VERSION 5.8 ;
BUSBITCHARS "[]" ;
DIVIDERCHAR "/" ;
UNITS
    DATABASE MICRONS 1000 ;
END UNITS

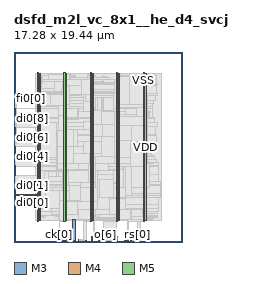
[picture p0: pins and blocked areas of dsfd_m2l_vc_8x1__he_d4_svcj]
MACRO dsfd_m2l_vc_8x1__he_d4_svcj
  FOREIGN dsfd_m2l_vc_8x1__he_d4_svcj 0 0 ;
  CLASS BLOCK ;
  SIZE 17.28 BY 19.44 ;
  PIN ck[0]
    DIRECTION INPUT ;
    USE SIGNAL ;
    PORT
      LAYER M3 ;
        RECT  4.644 0 4.662 0.144 ;
    END
    PORT
      LAYER M3 ;
        RECT  4.644 0.108 4.662 0.173 ;
    END
  END ck[0]
  PIN di0[0]
    DIRECTION INPUT ;
    USE SIGNAL ;
    PORT
      LAYER M4 ;
        RECT  0 4.8 0.192 4.824 ;
    END
    PORT
      LAYER M4 ;
        RECT  0.156 4.8 2.408 4.824 ;
    END
  END di0[0]
  PIN di0[1]
    DIRECTION INPUT ;
    USE SIGNAL ;
    PORT
      LAYER M4 ;
        RECT  0 5.808 0.192 5.832 ;
    END
  END di0[1]
  PIN di0[2]
    DIRECTION INPUT ;
    USE SIGNAL ;
    PORT
      LAYER M4 ;
        RECT  0 6.768 0.192 6.792 ;
    END
  END di0[2]
  PIN di0[3]
    DIRECTION INPUT ;
    USE SIGNAL ;
    PORT
      LAYER M4 ;
        RECT  0 7.776 0.192 7.8 ;
    END
  END di0[3]
  PIN di0[4]
    DIRECTION INPUT ;
    USE SIGNAL ;
    PORT
      LAYER M4 ;
        RECT  0 8.736 0.192 8.76 ;
    END
  END di0[4]
  PIN di0[5]
    DIRECTION INPUT ;
    USE SIGNAL ;
    PORT
      LAYER M4 ;
        RECT  0 9.744 0.192 9.768 ;
    END
  END di0[5]
  PIN di0[6]
    DIRECTION INPUT ;
    USE SIGNAL ;
    PORT
      LAYER M4 ;
        RECT  0 10.704 0.192 10.728 ;
    END
  END di0[6]
  PIN di0[7]
    DIRECTION INPUT ;
    USE SIGNAL ;
    PORT
      LAYER M4 ;
        RECT  0 11.712 0.192 11.736 ;
    END
  END di0[7]
  PIN di0[8]
    DIRECTION INPUT ;
    USE SIGNAL ;
    PORT
      LAYER M4 ;
        RECT  0 12.672 0.192 12.696 ;
    END
  END di0[8]
  PIN di0[9]
    DIRECTION INPUT ;
    USE SIGNAL ;
    PORT
      LAYER M4 ;
        RECT  0 13.68 0.192 13.704 ;
    END
  END di0[9]
  PIN fi0[0]
    DIRECTION INPUT ;
    USE SIGNAL ;
    PORT
      LAYER M4 ;
        RECT  0 14.64 0.192 14.664 ;
    END
  END fi0[0]
  PIN o[0]
    DIRECTION OUTPUT ;
    USE SIGNAL ;
    PORT
      LAYER M5 ;
        RECT  5.328 0 5.352 0.192 ;
    END
    PORT
      LAYER M5 ;
        RECT  4.656 0.144 5.352 0.323 ;
    END
  END o[0]
  PIN o[10]
    DIRECTION OUTPUT ;
    USE SIGNAL ;
    PORT
      LAYER M5 ;
        RECT  11.952 0 11.976 0.192 ;
    END
    PORT
      LAYER M5 ;
        RECT  11.952 0.144 11.976 0.227 ;
    END
  END o[10]
  PIN o[1]
    DIRECTION OUTPUT ;
    USE SIGNAL ;
    PORT
      LAYER M3 ;
        RECT  5.976 0 5.994 0.144 ;
    END
    PORT
      LAYER M3 ;
        RECT  5.976 0.108 5.994 0.139 ;
    END
    PORT
      LAYER M3 ;
        RECT  5.976 0.139 6.318 2.263 ;
    END
  END o[1]
  PIN o[2]
    DIRECTION OUTPUT ;
    USE SIGNAL ;
    PORT
      LAYER M5 ;
        RECT  6.624 0 6.648 0.192 ;
    END
    PORT
      LAYER M5 ;
        RECT  6.624 0.144 6.648 0.227 ;
    END
  END o[2]
  PIN o[3]
    DIRECTION OUTPUT ;
    USE SIGNAL ;
    PORT
      LAYER M3 ;
        RECT  7.308 0 7.326 0.144 ;
    END
    PORT
      LAYER M3 ;
        RECT  7.308 0.108 7.326 0.139 ;
    END
    PORT
      LAYER M3 ;
        RECT  7.308 0.139 7.398 0.187 ;
    END
  END o[3]
  PIN o[4]
    DIRECTION OUTPUT ;
    USE SIGNAL ;
    PORT
      LAYER M5 ;
        RECT  7.968 0 7.992 0.192 ;
    END
    PORT
      LAYER M5 ;
        RECT  7.968 0.144 7.992 0.563 ;
    END
  END o[4]
  PIN o[5]
    DIRECTION OUTPUT ;
    USE SIGNAL ;
    PORT
      LAYER M3 ;
        RECT  8.64 0 8.658 0.144 ;
    END
    PORT
      LAYER M3 ;
        RECT  8.64 0.108 8.658 0.139 ;
    END
    PORT
      LAYER M3 ;
        RECT  8.64 0.139 9.162 0.167 ;
    END
  END o[5]
  PIN o[6]
    DIRECTION OUTPUT ;
    USE SIGNAL ;
    PORT
      LAYER M5 ;
        RECT  9.312 0 9.336 0.192 ;
    END
    PORT
      LAYER M5 ;
        RECT  9.312 0.144 9.336 0.227 ;
    END
  END o[6]
  PIN o[7]
    DIRECTION OUTPUT ;
    USE SIGNAL ;
    PORT
      LAYER M3 ;
        RECT  9.972 0 9.99 0.144 ;
    END
    PORT
      LAYER M3 ;
        RECT  9.972 0.108 9.99 0.139 ;
    END
    PORT
      LAYER M3 ;
        RECT  9.972 0.139 10.386 0.187 ;
    END
  END o[7]
  PIN o[8]
    DIRECTION OUTPUT ;
    USE SIGNAL ;
    PORT
      LAYER M5 ;
        RECT  10.608 0 10.632 0.192 ;
    END
    PORT
      LAYER M5 ;
        RECT  10.608 0.144 10.632 0.563 ;
    END
  END o[8]
  PIN o[9]
    DIRECTION OUTPUT ;
    USE SIGNAL ;
    PORT
      LAYER M3 ;
        RECT  11.304 0 11.322 0.144 ;
    END
    PORT
      LAYER M3 ;
        RECT  11.304 0.108 11.322 0.139 ;
    END
    PORT
      LAYER M3 ;
        RECT  11.304 0.139 11.682 0.167 ;
    END
  END o[9]
  PIN rs[0]
    DIRECTION INPUT ;
    USE SIGNAL ;
    PORT
      LAYER M3 ;
        RECT  12.636 0 12.654 0.144 ;
    END
    PORT
      LAYER M3 ;
        RECT  12.636 0.108 12.654 0.187 ;
    END
  END rs[0]
  PIN VDD
    DIRECTION INOUT ;
    USE POWER ;
    PORT
      LAYER M5 ;
        RECT  13.392 2.151 13.512 17.289 ;
        RECT  10.692 2.151 10.812 17.289 ;
        RECT  7.992 2.151 8.112 17.289 ;
        RECT  5.292 2.151 5.412 17.289 ;
        RECT  2.592 2.151 2.712 17.289 ;
    END
  END VDD
  PIN VSS
    DIRECTION INOUT ;
    USE GROUND ;
    PORT
      LAYER M5 ;
        RECT  13.2 2.137 13.32 17.303 ;
        RECT  10.5 2.137 10.62 17.303 ;
        RECT  7.8 2.137 7.92 17.303 ;
        RECT  5.1 2.137 5.22 17.303 ;
        RECT  2.4 2.137 2.52 17.303 ;
    END
  END VSS
  # OT_OBS_CLOSED layer=M5 d_um=1.536 added=44
  OBS
    LAYER RVTN ;
     RECT  2.16 2.16 15.12 2.295 ;
     RECT  2.16 2.565 15.12 2.835 ;
     RECT  2.16 3.105 15.12 3.375 ;
     RECT  2.16 3.645 15.12 3.915 ;
     RECT  2.16 4.185 15.12 4.455 ;
     RECT  2.16 4.725 15.12 4.995 ;
     RECT  2.16 5.265 15.12 5.535 ;
     RECT  2.16 5.805 15.12 6.075 ;
     RECT  2.16 6.345 15.12 6.615 ;
     RECT  2.16 6.885 15.12 7.155 ;
     RECT  2.16 7.425 15.12 7.695 ;
     RECT  2.16 7.965 15.12 8.235 ;
     RECT  2.16 8.505 15.12 8.775 ;
     RECT  2.16 9.045 15.12 9.315 ;
     RECT  2.16 9.585 15.12 9.855 ;
     RECT  2.16 10.125 15.12 10.395 ;
     RECT  2.16 10.665 15.12 10.935 ;
     RECT  2.16 11.205 15.12 11.475 ;
     RECT  2.16 11.745 15.12 12.015 ;
     RECT  2.16 12.285 15.12 12.555 ;
     RECT  2.16 12.825 15.12 13.095 ;
     RECT  2.16 13.365 15.12 13.635 ;
     RECT  2.16 13.905 15.12 14.175 ;
     RECT  2.16 14.445 15.12 14.715 ;
     RECT  2.16 14.985 15.12 15.255 ;
     RECT  2.16 15.525 15.12 15.795 ;
     RECT  2.16 16.065 15.12 16.335 ;
     RECT  2.16 16.605 15.12 16.875 ;
     RECT  2.16 17.145 15.12 17.28 ;
    LAYER RVTP ;
     RECT  2.16 2.295 15.12 2.565 ;
     RECT  2.16 2.835 15.12 3.105 ;
     RECT  2.16 3.375 15.12 3.645 ;
     RECT  2.16 3.915 15.12 4.185 ;
     RECT  2.16 4.455 15.12 4.725 ;
     RECT  2.16 4.995 15.12 5.265 ;
     RECT  2.16 5.535 15.12 5.805 ;
     RECT  2.16 6.075 15.12 6.345 ;
     RECT  2.16 6.615 15.12 6.885 ;
     RECT  2.16 7.155 15.12 7.425 ;
     RECT  2.16 7.695 15.12 7.965 ;
     RECT  2.16 8.235 15.12 8.505 ;
     RECT  2.16 8.775 15.12 9.045 ;
     RECT  2.16 9.315 15.12 9.585 ;
     RECT  2.16 9.855 15.12 10.125 ;
     RECT  2.16 10.395 15.12 10.665 ;
     RECT  2.16 10.935 15.12 11.205 ;
     RECT  2.16 11.475 15.12 11.745 ;
     RECT  2.16 12.015 15.12 12.285 ;
     RECT  2.16 12.555 15.12 12.825 ;
     RECT  2.16 13.095 15.12 13.365 ;
     RECT  2.16 13.635 15.12 13.905 ;
     RECT  2.16 14.175 15.12 14.445 ;
     RECT  2.16 14.715 15.12 14.985 ;
     RECT  2.16 15.255 15.12 15.525 ;
     RECT  2.16 15.795 15.12 16.065 ;
     RECT  2.16 16.335 15.12 16.605 ;
     RECT  2.16 16.875 15.12 17.145 ;
    LAYER M1 ;
     RECT  2.16 2.151 15.12 17.289 ;
    LAYER M2 ;
     RECT  5.971 0.144 6.323 0.162 ;
     RECT  7.303 0.144 7.403 0.162 ;
     RECT  8.635 0.144 9.167 0.162 ;
     RECT  9.967 0.144 10.391 0.162 ;
     RECT  11.299 0.144 11.687 0.162 ;
     RECT  2.16 2.151 12.343 17.289 ;
     RECT  12.343 2.106 12.659 17.289 ;
     RECT  12.659 2.151 15.12 17.289 ;
    LAYER M3 ;
     RECT  9.144 0.167 9.162 0.187 ;
     RECT  9.144 0.187 10.386 0.523 ;
     RECT  11.664 0.167 11.682 2.101 ;
     RECT  12.636 0.187 12.978 2.101 ;
     RECT  7.128 0.187 7.398 2.143 ;
     RECT  8.172 0.523 8.19 2.143 ;
     RECT  9.144 0.523 10.494 2.143 ;
     RECT  11.664 2.101 12.978 2.143 ;
     RECT  7.128 2.143 8.19 2.227 ;
     RECT  9.144 2.143 10.605 2.227 ;
     RECT  5.115 2.143 5.205 2.263 ;
     RECT  11.664 2.143 13.305 2.263 ;
     RECT  5.115 2.263 6.318 2.299 ;
     RECT  7.128 2.227 10.605 2.299 ;
     RECT  11.52 2.263 13.305 2.299 ;
     RECT  4.644 2.299 13.305 2.335 ;
     RECT  14.184 2.227 14.202 2.335 ;
     RECT  4.536 2.335 14.202 2.371 ;
     RECT  2.415 2.143 2.505 2.413 ;
     RECT  2.415 2.413 2.697 2.533 ;
     RECT  4.536 2.371 14.274 2.533 ;
     RECT  2.415 2.533 3.15 2.605 ;
     RECT  4.536 2.533 14.634 2.605 ;
     RECT  2.415 2.605 3.258 2.731 ;
     RECT  4.248 2.605 14.634 2.731 ;
     RECT  2.415 2.731 14.634 3.109 ;
     RECT  2.415 3.109 14.742 3.451 ;
     RECT  2.376 3.451 14.814 3.839 ;
     RECT  2.415 3.839 14.814 4.531 ;
     RECT  2.415 4.531 14.994 4.795 ;
     RECT  2.304 4.795 14.994 4.955 ;
     RECT  2.415 4.955 14.994 5.803 ;
     RECT  2.304 5.803 14.994 5.873 ;
     RECT  2.415 5.873 14.994 6.143 ;
     RECT  2.415 6.143 14.742 6.893 ;
     RECT  2.415 6.893 11.25 7.723 ;
     RECT  11.988 6.893 14.742 7.723 ;
     RECT  2.415 7.723 14.742 7.735 ;
     RECT  2.415 7.735 14.814 7.861 ;
     RECT  2.376 7.861 14.814 8.159 ;
     RECT  2.376 8.159 14.562 8.429 ;
     RECT  2.376 8.429 14.382 8.731 ;
     RECT  2.304 8.731 14.382 8.879 ;
     RECT  2.304 8.879 14.094 9.005 ;
     RECT  2.376 9.005 14.094 9.739 ;
     RECT  2.304 9.739 14.094 10.165 ;
     RECT  2.304 10.165 14.562 10.895 ;
     RECT  2.415 10.895 14.562 11.003 ;
     RECT  2.415 11.003 14.526 11.785 ;
     RECT  2.415 11.785 14.634 12.209 ;
     RECT  2.415 12.209 14.526 12.245 ;
     RECT  2.415 12.245 14.346 12.667 ;
     RECT  2.412 12.667 14.346 12.749 ;
     RECT  2.412 12.749 14.166 12.785 ;
     RECT  2.415 12.785 14.166 13.675 ;
     RECT  2.304 13.675 14.166 13.865 ;
     RECT  2.376 13.865 14.166 14.179 ;
     RECT  2.376 14.179 14.31 14.449 ;
     RECT  2.376 14.449 14.526 14.989 ;
     RECT  2.376 14.989 14.634 15.179 ;
     RECT  2.376 15.179 11.826 15.341 ;
     RECT  2.376 15.341 11.718 15.449 ;
     RECT  4.896 15.449 11.718 15.557 ;
     RECT  2.376 15.449 4.158 15.719 ;
     RECT  12.708 15.179 14.562 15.997 ;
     RECT  12.636 15.997 14.562 16.105 ;
     RECT  4.932 15.557 11.718 16.141 ;
     RECT  12.636 16.105 14.706 16.141 ;
     RECT  4.932 16.141 14.706 16.259 ;
     RECT  2.415 15.719 4.158 16.411 ;
     RECT  4.932 16.259 14.562 16.411 ;
     RECT  2.415 16.411 14.562 16.673 ;
     RECT  2.415 16.673 9.774 16.835 ;
     RECT  2.415 16.835 8.298 16.871 ;
     RECT  9.072 16.835 9.486 16.871 ;
     RECT  9.072 16.871 9.45 16.943 ;
     RECT  2.415 16.871 6.318 16.979 ;
     RECT  2.415 16.979 3.582 17.069 ;
     RECT  4.356 16.979 6.318 17.069 ;
     RECT  7.56 16.871 8.298 17.069 ;
     RECT  9.072 16.943 9.09 17.069 ;
     RECT  10.515 16.673 14.562 17.069 ;
     RECT  7.56 17.069 8.154 17.105 ;
     RECT  11.808 17.069 11.826 17.105 ;
     RECT  12.888 17.069 13.986 17.105 ;
     RECT  3.564 17.069 3.582 17.117 ;
     RECT  4.356 17.069 4.374 17.117 ;
     RECT  5.115 17.069 5.742 17.117 ;
     RECT  10.515 17.069 10.854 17.117 ;
     RECT  13.032 17.105 13.305 17.117 ;
     RECT  2.415 17.069 2.505 17.297 ;
     RECT  5.115 17.117 5.205 17.297 ;
     RECT  7.815 17.105 7.905 17.297 ;
     RECT  10.515 17.117 10.605 17.297 ;
     RECT  13.215 17.117 13.305 17.297 ;
    LAYER M4 ;
     RECT  0.156 13.68 0.275 14.664 ;
     RECT  0.156 7.776 2.365 8.76 ;
     RECT  0.156 9.744 2.365 10.728 ;
     RECT  0.156 5.808 2.408 6.792 ;
     RECT  2.365 7.776 2.408 10.728 ;
     RECT  0.156 11.712 2.408 12.696 ;
     RECT  0.275 13.68 2.408 13.704 ;
     RECT  2.365 15.024 2.408 15.048 ;
     RECT  2.408 2.148 2.512 17.292 ;
     RECT  2.512 2.418 2.704 17.022 ;
     RECT  2.704 15.024 2.801 17.022 ;
     RECT  2.801 16.32 2.873 17.022 ;
     RECT  2.704 5.088 3.521 7.32 ;
     RECT  2.873 16.608 3.553 17.022 ;
     RECT  2.801 15.024 3.731 15.048 ;
     RECT  3.685 13.968 3.772 13.992 ;
     RECT  2.704 3.456 3.805 3.48 ;
     RECT  3.805 2.832 3.845 3.48 ;
     RECT  3.521 5.088 3.985 5.544 ;
     RECT  3.521 6.672 4.345 7.32 ;
     RECT  2.704 8.688 4.345 12.216 ;
     RECT  4.345 6.672 4.549 12.216 ;
     RECT  4.604 0.144 4.691 0.168 ;
     RECT  3.985 4.176 4.981 5.544 ;
     RECT  4.549 6.672 4.981 12.888 ;
     RECT  3.845 2.832 5.108 2.856 ;
     RECT  4.981 4.176 5.108 12.888 ;
     RECT  4.237 14.256 5.108 14.424 ;
     RECT  3.553 16.608 5.108 17.112 ;
     RECT  5.108 2.148 5.212 17.292 ;
     RECT  5.212 2.418 5.404 17.112 ;
     RECT  5.404 15.984 5.689 17.112 ;
     RECT  5.404 13.68 5.692 15 ;
     RECT  5.689 16.56 5.753 17.112 ;
     RECT  5.317 0.288 6.005 0.312 ;
     RECT  5.404 3.312 6.131 11.544 ;
     RECT  6.131 9.504 6.473 11.544 ;
     RECT  6.131 3.312 6.505 7.992 ;
     RECT  6.505 2.784 6.527 7.992 ;
     RECT  5.404 12.528 6.541 12.552 ;
     RECT  5.692 13.68 6.541 13.704 ;
     RECT  6.541 12.528 6.581 13.704 ;
     RECT  6.527 2.304 6.589 7.992 ;
     RECT  5.692 14.784 6.86 15 ;
     RECT  5.753 16.56 6.901 16.632 ;
     RECT  6.473 9.504 7.109 10.296 ;
     RECT  6.473 11.52 7.117 11.544 ;
     RECT  6.581 13.392 7.153 13.704 ;
     RECT  6.86 14.784 7.153 15.096 ;
     RECT  6.613 0.192 7.157 0.216 ;
     RECT  6.589 3.312 7.669 7.992 ;
     RECT  7.109 9.072 7.669 10.296 ;
     RECT  6.589 2.304 7.765 2.328 ;
     RECT  7.765 2.256 7.808 2.328 ;
     RECT  7.669 3.312 7.808 10.296 ;
     RECT  7.117 11.52 7.808 12.312 ;
     RECT  7.153 13.392 7.808 15.096 ;
     RECT  6.901 16.08 7.808 16.632 ;
     RECT  7.808 2.148 7.912 17.292 ;
     RECT  7.912 2.256 8.104 17.022 ;
     RECT  8.104 16.368 8.165 16.632 ;
     RECT  7.957 0.528 8.201 0.552 ;
     RECT  8.104 2.256 8.291 14.76 ;
     RECT  8.291 2.544 8.561 14.76 ;
     RECT  8.561 2.544 8.705 6.36 ;
     RECT  8.561 7.344 8.963 14.76 ;
     RECT  8.963 10.8 9.059 14.76 ;
     RECT  9.059 12 9.137 14.76 ;
     RECT  8.165 16.368 9.205 16.392 ;
     RECT  9.137 12 9.425 12.024 ;
     RECT  9.301 0.192 9.749 0.216 ;
     RECT  8.963 7.344 10.033 9.528 ;
     RECT  9.059 10.8 10.033 10.968 ;
     RECT  9.137 13.392 10.172 14.76 ;
     RECT  10.172 13.392 10.249 15.192 ;
     RECT  8.705 2.544 10.261 2.808 ;
     RECT  8.705 3.84 10.261 6.36 ;
     RECT  10.249 12.864 10.261 15.192 ;
     RECT  9.205 16.368 10.261 16.584 ;
     RECT  10.033 7.344 10.357 10.968 ;
     RECT  10.261 2.544 10.508 6.36 ;
     RECT  10.357 7.344 10.508 11.496 ;
     RECT  10.261 12.864 10.508 16.584 ;
     RECT  10.508 2.148 10.612 17.292 ;
     RECT  10.465 0.528 10.643 0.552 ;
     RECT  10.612 2.418 10.804 17.112 ;
     RECT  10.804 16.56 10.865 17.112 ;
     RECT  10.804 4.512 11.164 9.624 ;
     RECT  11.164 8.784 11.225 9.624 ;
     RECT  11.164 4.512 11.441 7.752 ;
     RECT  10.804 13.104 11.513 14.136 ;
     RECT  11.513 13.104 11.549 13.128 ;
     RECT  10.804 10.944 11.621 11.688 ;
     RECT  10.804 2.418 11.761 3.384 ;
     RECT  11.513 14.112 11.843 14.136 ;
     RECT  10.804 15.312 11.843 15.336 ;
     RECT  10.865 16.848 11.881 16.872 ;
     RECT  11.225 8.784 11.939 8.808 ;
     RECT  11.441 4.8 11.981 7.752 ;
     RECT  11.761 2.352 11.987 3.384 ;
     RECT  11.969 11.904 12.013 11.928 ;
     RECT  11.893 10.272 12.035 10.872 ;
     RECT  12.035 10.272 12.053 10.344 ;
     RECT  12.013 11.904 12.517 12.888 ;
     RECT  11.941 0.192 12.989 0.216 ;
     RECT  11.987 2.352 13.093 2.376 ;
     RECT  11.987 3.36 13.093 3.384 ;
     RECT  13.093 2.352 13.208 3.384 ;
     RECT  12.589 4.512 13.208 4.536 ;
     RECT  11.981 5.568 13.208 7.752 ;
     RECT  12.053 10.272 13.208 10.296 ;
     RECT  12.517 11.904 13.208 13.704 ;
     RECT  13.021 16.752 13.208 17.112 ;
     RECT  13.208 2.148 13.312 17.292 ;
     RECT  13.312 2.352 13.504 17.022 ;
     RECT  13.504 12.864 13.529 15 ;
     RECT  13.504 2.352 13.601 2.904 ;
     RECT  13.529 14.4 13.619 15 ;
     RECT  13.504 10.368 13.637 10.392 ;
     RECT  13.504 7.728 13.66 8.856 ;
     RECT  13.504 5.568 13.667 6.12 ;
     RECT  13.504 4.512 13.673 4.536 ;
     RECT  13.66 7.728 13.673 8.616 ;
     RECT  13.619 14.976 13.673 15 ;
     RECT  13.529 12.864 13.781 13.32 ;
     RECT  13.781 12.96 13.817 13.32 ;
     RECT  13.667 5.568 13.859 5.88 ;
     RECT  13.673 7.728 13.889 8.04 ;
     RECT  13.859 5.856 13.9 5.88 ;
     RECT  13.817 13.296 13.961 13.32 ;
     RECT  13.504 16.896 13.997 16.92 ;
     RECT  13.889 8.016 14.285 8.04 ;
     RECT  13.601 2.88 14.501 2.904 ;
    LAYER M5 ;
     RECT  4.656 0.133 4.68 0.144 ;
     RECT  4.656 0.323 4.68 2.137 ;
     RECT  2.4 2.137 2.52 2.151 ;
     RECT  4.656 2.137 5.22 2.151 ;
     RECT  7.8 2.137 7.92 2.151 ;
     RECT  10.5 2.137 10.62 2.151 ;
     RECT  13.2 2.137 13.32 2.151 ;
     RECT  7.8 2.151 8.112 2.245 ;
     RECT  10.5 2.151 10.812 2.533 ;
     RECT  13.2 2.151 13.512 2.581 ;
     RECT  6.576 2.293 6.6 2.773 ;
     RECT  10.272 2.533 10.812 2.773 ;
     RECT  7.8 2.245 8.28 2.821 ;
     RECT  11.952 2.341 11.976 3.347 ;
     RECT  6.528 2.773 6.6 3.349 ;
     RECT  7.8 2.821 8.328 3.349 ;
     RECT  13.104 2.581 13.512 3.395 ;
     RECT  2.4 2.151 2.712 3.445 ;
     RECT  6.528 3.349 8.568 4.163 ;
     RECT  4.656 2.151 5.412 4.213 ;
     RECT  9.792 2.773 10.812 4.501 ;
     RECT  9.792 4.501 11.4 4.595 ;
     RECT  4.656 4.213 5.688 5.315 ;
     RECT  2.4 3.445 3.192 5.459 ;
     RECT  13.2 3.395 13.512 5.557 ;
     RECT  6.816 4.163 8.568 5.603 ;
     RECT  10.224 4.595 11.4 5.603 ;
     RECT  4.992 5.315 5.688 5.747 ;
     RECT  10.224 5.603 10.812 5.987 ;
     RECT  6.816 5.603 8.376 6.083 ;
     RECT  10.368 5.987 10.812 6.083 ;
     RECT  4.992 5.747 5.544 7.189 ;
     RECT  2.4 5.459 3.144 7.331 ;
     RECT  4.416 7.189 5.544 7.333 ;
     RECT  10.5 6.083 10.812 7.333 ;
     RECT  9.696 7.333 10.812 7.381 ;
     RECT  4.416 7.333 6.12 7.429 ;
     RECT  9.696 7.381 11.112 7.717 ;
     RECT  4.416 7.429 6.552 8.003 ;
     RECT  7.632 6.083 8.376 8.003 ;
     RECT  9.696 7.717 11.928 8.003 ;
     RECT  13.2 5.557 13.848 8.003 ;
     RECT  13.2 8.003 13.656 8.051 ;
     RECT  10.32 8.003 11.928 8.675 ;
     RECT  7.68 8.003 8.376 8.773 ;
     RECT  7.68 8.773 8.952 9.061 ;
     RECT  4.416 8.003 6.12 9.779 ;
     RECT  11.904 8.675 11.928 10.261 ;
     RECT  7.152 9.061 8.952 10.307 ;
     RECT  11.904 10.261 12.024 10.355 ;
     RECT  7.8 10.307 8.952 10.789 ;
     RECT  4.416 9.779 5.412 11.459 ;
     RECT  12 10.355 12.024 11.939 ;
     RECT  7.8 10.789 9.048 12.035 ;
     RECT  13.2 8.051 13.608 12.853 ;
     RECT  4.56 11.459 5.412 12.899 ;
     RECT  10.32 8.675 10.812 13.093 ;
     RECT  10.32 13.093 11.4 13.381 ;
     RECT  7.8 12.035 8.952 13.427 ;
     RECT  10.224 13.381 11.4 13.667 ;
     RECT  7.8 13.427 8.232 13.715 ;
     RECT  12.528 12.853 13.608 13.715 ;
     RECT  5.1 12.899 5.412 14.101 ;
     RECT  7.8 13.715 8.112 14.389 ;
     RECT  13.2 13.715 13.608 14.435 ;
     RECT  0.24 10.069 0.264 14.675 ;
     RECT  3.696 13.957 3.72 15.059 ;
     RECT  7.296 14.389 8.112 15.061 ;
     RECT  10.224 13.667 10.812 15.203 ;
     RECT  5.1 14.101 5.64 16.019 ;
     RECT  10.272 15.203 10.812 16.595 ;
     RECT  6.912 15.061 8.112 16.643 ;
     RECT  11.808 14.101 11.832 16.883 ;
     RECT  2.4 7.331 2.712 17.289 ;
     RECT  5.1 16.019 5.412 17.289 ;
     RECT  7.8 16.643 8.112 17.289 ;
     RECT  10.5 16.595 10.812 17.289 ;
     RECT  13.2 14.435 13.512 17.289 ;
     RECT  2.4 17.289 2.52 17.303 ;
     RECT  5.1 17.289 5.22 17.303 ;
     RECT  7.8 17.289 7.92 17.303 ;
     RECT  10.5 17.289 10.62 17.303 ;
     RECT  13.2 17.289 13.32 17.303 ;
     RECT  5.412 2.293 6.576 2.773 ;
     RECT  6.6 2.293 7.8 3.349 ;
     RECT  10.812 2.341 11.952 3.347 ;
     RECT  11.976 2.341 13.2 2.581 ;
     RECT  11.976 2.581 13.104 3.347 ;
     RECT  5.412 2.773 6.528 4.163 ;
     RECT  8.28 2.773 9.792 2.821 ;
     RECT  8.328 2.821 9.792 3.349 ;
     RECT  10.812 3.347 11.4 4.501 ;
     RECT  8.568 3.349 9.792 4.595 ;
     RECT  3.192 3.445 4.656 5.315 ;
     RECT  5.412 4.163 6.816 4.213 ;
     RECT  5.688 4.213 6.816 5.747 ;
     RECT  5.544 5.747 6.816 6.083 ;
     RECT  10.224 5.987 10.368 6.083 ;
     RECT  5.544 6.083 7.632 7.333 ;
     RECT  10.224 6.083 10.5 7.333 ;
     RECT  3.144 7.189 4.416 7.331 ;
     RECT  6.12 7.333 7.632 7.429 ;
     RECT  8.376 7.333 9.696 8.003 ;
     RECT  6.552 7.429 7.632 8.003 ;
     RECT  11.928 7.717 13.2 10.261 ;
     RECT  6.12 8.003 7.68 9.061 ;
     RECT  8.376 8.003 10.32 8.773 ;
     RECT  10.812 8.675 11.904 10.355 ;
     RECT  8.952 8.773 10.32 10.789 ;
     RECT  6.12 9.061 7.152 9.779 ;
     RECT  12.024 10.261 13.2 11.939 ;
     RECT  10.812 10.355 12 11.939 ;
     RECT  9.048 10.789 10.32 12.035 ;
     RECT  10.812 11.939 13.2 12.853 ;
     RECT  8.952 12.035 10.32 13.381 ;
     RECT  10.812 12.853 12.528 13.093 ;
     RECT  4.56 12.899 5.1 13.957 ;
     RECT  11.4 13.093 12.528 13.667 ;
     RECT  8.952 13.381 10.224 13.427 ;
     RECT  10.812 13.667 12.528 13.715 ;
     RECT  10.812 13.715 13.2 14.101 ;
     RECT  2.712 13.957 3.696 15.059 ;
     RECT  3.72 13.957 5.1 15.059 ;
     RECT  10.812 14.101 11.808 16.883 ;
     RECT  11.832 14.101 13.2 16.883 ;
     RECT  5.64 15.061 6.912 16.019 ;
     RECT  5.412 16.019 6.912 16.643 ;
  END
END dsfd_m2l_vc_8x1__he_d4_svcj
END LIBRARY
